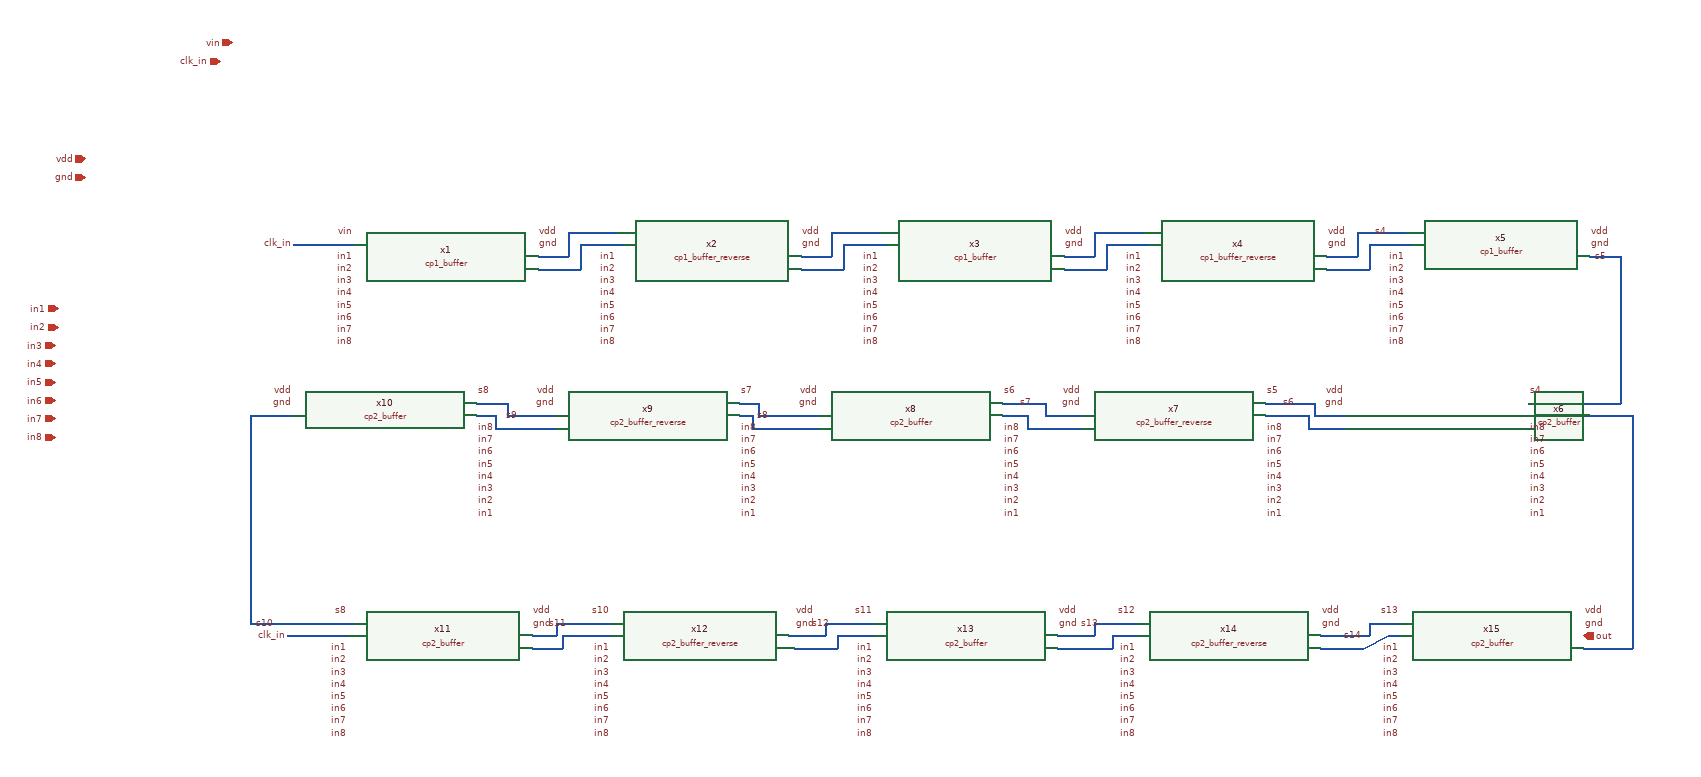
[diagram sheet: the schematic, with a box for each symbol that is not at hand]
v {xschem version=3.4.4 file_version=1.2
}
G {}
K {}
V {}
S {}
E {}
N -850 -580 -750 -580 {
lab=clk_in}
N -450 -560 -400 -560 {
lab=#net1}
N -400 -580 -400 -560 {
lab=#net1}
N -400 -600 -400 -580 {
lab=#net1}
N -400 -600 -320 -600 {
lab=#net1}
N -450 -540 -380 -540 {
lab=#net2}
N -380 -580 -380 -540 {
lab=#net2}
N -380 -580 -310 -580 {
lab=#net2}
N -20 -560 30 -560 {
lab=#net3}
N 30 -580 30 -560 {
lab=#net3}
N 30 -600 30 -580 {
lab=#net3}
N 30 -600 110 -600 {
lab=#net3}
N -20 -540 50 -540 {
lab=#net4}
N 50 -580 50 -540 {
lab=#net4}
N 50 -580 120 -580 {
lab=#net4}
N 410 -560 460 -560 {
lab=#net5}
N 460 -580 460 -560 {
lab=#net5}
N 460 -600 460 -580 {
lab=#net5}
N 460 -600 540 -600 {
lab=#net5}
N 410 -540 480 -540 {
lab=#net6}
N 480 -580 480 -540 {
lab=#net6}
N 480 -580 550 -580 {
lab=#net6}
N 840 -560 890 -560 {
lab=s4}
N 890 -580 890 -560 {
lab=s4}
N 890 -600 890 -580 {
lab=s4}
N 890 -600 970 -600 {
lab=s4}
N 840 -540 910 -540 {
lab=#net7}
N 910 -580 910 -540 {
lab=#net7}
N 910 -580 980 -580 {
lab=#net7}
N 1170 -300 1270 -300 {
lab=#net8}
N -860 60 -760 60 {
lab=clk_in}
N -500 -300 -420 -300 {
lab=s9}
N -500 -320 -500 -300 {
lab=s9}
N -540 -320 -500 -320 {
lab=s9}
N -550 -320 -540 -320 {
lab=s9}
N -90 -300 10 -300 {
lab=s8}
N -90 -320 -90 -300 {
lab=s8}
N -120 -320 -90 -320 {
lab=s8}
N -520 -280 -420 -280 {
lab=#net9}
N -520 -300 -520 -280 {
lab=#net9}
N -550 -300 -520 -300 {
lab=#net9}
N -100 -280 10 -280 {
lab=#net10}
N -100 -300 -100 -280 {
lab=#net10}
N -120 -300 -100 -300 {
lab=#net10}
N 350 -280 440 -280 {
lab=#net11}
N 350 -300 350 -280 {
lab=#net11}
N 310 -300 350 -300 {
lab=#net11}
N 810 -280 870 -280 {
lab=#net12}
N 810 -300 810 -280 {
lab=#net12}
N 740 -300 810 -300 {
lab=#net12}
N 1260 80 1340 80 {
lab=#net8}
N 1340 -300 1340 80 {
lab=#net8}
N 1260 -300 1340 -300 {
lab=#net8}
N 740 -320 820 -320 {
lab=s6}
N -460 80 -410 80 {
lab=#net13}
N -410 60 -410 80 {
lab=#net13}
N -410 60 -330 60 {
lab=#net13}
N -30 80 40 80 {
lab=#net14}
N 90 60 100 60 {
lab=#net14}
N 40 60 90 60 {
lab=#net14}
N 40 60 40 80 {
lab=#net14}
N 380 -300 440 -300 {
lab=s7}
N 380 -320 380 -300 {
lab=s7}
N 310 -320 380 -320 {
lab=s7}
N 1270 -560 1320 -560 {
lab=s5}
N 1320 -560 1320 -320 {
lab=s5}
N 1170 -320 1320 -320 {
lab=s5}
N -920 -300 -850 -300 {
lab=s10}
N -920 -300 -920 40 {
lab=s10}
N -920 40 -750 40 {
lab=s10}
N -460 60 -420 60 {
lab=s11}
N -420 40 -420 60 {
lab=s11}
N -420 40 -330 40 {
lab=s11}
N -40 60 -30 60 {
lab=s12}
N -30 60 20 60 {
lab=s12}
N 20 40 20 60 {
lab=s12}
N 20 40 100 40 {
lab=s12}
N 400 60 460 60 {
lab=s13}
N 460 40 460 60 {
lab=s13}
N 460 40 530 40 {
lab=s13}
N 830 60 910 60 {
lab=s14}
N 910 40 910 60 {
lab=s14}
N 910 40 960 40 {
lab=s14}
N 400 80 490 80 {
lab=#net15}
N 490 60 490 80 {
lab=#net15}
N 490 60 530 60 {
lab=#net15}
N 820 -320 820 -300 {
lab=s6}
N 820 -300 870 -300 {
lab=s6}
N 830 80 900 80 {
lab=#net16}
N 900 80 940 60 {
lab=#net16}
N 940 60 960 60 {
lab=#net16}
C {cp1_buffer.sym} -600 -510 0 0 {name=x1}
C {devices/lab_pin.sym} -750 -560 0 0 {name=p145 sig_type=std_logic lab=in1
value=0}
C {devices/lab_pin.sym} -750 -540 0 0 {name=p146 sig_type=std_logic lab=in2
value=0}
C {devices/lab_pin.sym} -750 -520 0 0 {name=p147 sig_type=std_logic lab=in3
value=0}
C {devices/lab_pin.sym} -750 -500 0 0 {name=p148 sig_type=std_logic lab=in4
value=0}
C {devices/lab_pin.sym} -750 -480 0 0 {name=p149 sig_type=std_logic lab=in5
value=0}
C {devices/lab_pin.sym} -750 -460 0 0 {name=p150 sig_type=std_logic lab=in6
value=0}
C {devices/lab_pin.sym} -750 -440 0 0 {name=p151 sig_type=std_logic lab=in7
value=0}
C {devices/lab_pin.sym} -750 -420 0 0 {name=p152 sig_type=std_logic lab=in8
value=0}
C {devices/lab_pin.sym} -750 -600 0 0 {name=p153 sig_type=std_logic lab=vin}
C {devices/lab_pin.sym} -850 -580 0 0 {name=p1 sig_type=std_logic lab=clk_in}
C {cp1_buffer.sym} 260 -510 0 0 {name=x3}
C {devices/lab_pin.sym} 110 -560 0 0 {name=p2 sig_type=std_logic lab=in1
value=0}
C {devices/lab_pin.sym} 110 -540 0 0 {name=p3 sig_type=std_logic lab=in2
value=0}
C {devices/lab_pin.sym} 110 -520 0 0 {name=p12 sig_type=std_logic lab=in3
value=0}
C {devices/lab_pin.sym} 110 -500 0 0 {name=p15 sig_type=std_logic lab=in4
value=0}
C {devices/lab_pin.sym} 110 -480 0 0 {name=p16 sig_type=std_logic lab=in5
value=0}
C {devices/lab_pin.sym} 110 -460 0 0 {name=p17 sig_type=std_logic lab=in6
value=0}
C {devices/lab_pin.sym} 110 -440 0 0 {name=p18 sig_type=std_logic lab=in7
value=0}
C {devices/lab_pin.sym} 110 -420 0 0 {name=p19 sig_type=std_logic lab=in8
value=0}
C {devices/lab_pin.sym} 410 -600 2 0 {name=p20 sig_type=std_logic lab=vdd}
C {devices/lab_pin.sym} 410 -580 2 0 {name=p21 sig_type=std_logic lab=gnd}
C {cp1_buffer.sym} 1120 -510 0 0 {name=x5}
C {devices/lab_pin.sym} 970 -560 0 0 {name=p28 sig_type=std_logic lab=in1
value=0}
C {devices/lab_pin.sym} 970 -540 0 0 {name=p29 sig_type=std_logic lab=in2
value=0}
C {devices/lab_pin.sym} 970 -520 0 0 {name=p30 sig_type=std_logic lab=in3
value=0}
C {devices/lab_pin.sym} 970 -500 0 0 {name=p31 sig_type=std_logic lab=in4
value=0}
C {devices/lab_pin.sym} 970 -480 0 0 {name=p32 sig_type=std_logic lab=in5
value=0}
C {devices/lab_pin.sym} 970 -460 0 0 {name=p33 sig_type=std_logic lab=in6
value=0}
C {devices/lab_pin.sym} 970 -440 0 0 {name=p34 sig_type=std_logic lab=in7
value=0}
C {devices/lab_pin.sym} 970 -420 0 0 {name=p35 sig_type=std_logic lab=in8
value=0}
C {devices/lab_pin.sym} 1270 -600 2 0 {name=p36 sig_type=std_logic lab=vdd}
C {devices/lab_pin.sym} 1270 -580 2 0 {name=p37 sig_type=std_logic lab=gnd}
C {devices/lab_pin.sym} -20 -600 2 0 {name=p38 sig_type=std_logic lab=vdd}
C {devices/lab_pin.sym} -20 -580 2 0 {name=p39 sig_type=std_logic lab=gnd}
C {devices/lab_pin.sym} -450 -600 2 0 {name=p40 sig_type=std_logic lab=vdd}
C {devices/lab_pin.sym} -450 -580 2 0 {name=p41 sig_type=std_logic lab=gnd}
C {devices/lab_pin.sym} 840 -600 2 0 {name=p42 sig_type=std_logic lab=vdd}
C {devices/lab_pin.sym} 840 -580 2 0 {name=p43 sig_type=std_logic lab=gnd}
C {cp2_buffer.sym} 1020 -240 0 1 {name=x6}
C {cp2_buffer_reverse.sym} 590 -240 0 1 {name=x7}
C {cp2_buffer.sym} 160 -240 0 1 {name=x8}
C {devices/lab_pin.sym} 10 -340 2 1 {name=p70 sig_type=std_logic lab=vdd}
C {devices/lab_pin.sym} 10 -320 2 1 {name=p71 sig_type=std_logic lab=gnd}
C {cp2_buffer_reverse.sym} -270 -240 0 1 {name=x9}
C {cp2_buffer.sym} -700 -240 0 1 {name=x10}
C {devices/lab_pin.sym} -850 -340 2 1 {name=p88 sig_type=std_logic lab=vdd}
C {devices/lab_pin.sym} -850 -320 2 1 {name=p89 sig_type=std_logic lab=gnd}
C {devices/lab_pin.sym} 440 -340 2 1 {name=p90 sig_type=std_logic lab=vdd}
C {devices/lab_pin.sym} 440 -320 2 1 {name=p91 sig_type=std_logic lab=gnd}
C {devices/lab_pin.sym} 870 -340 2 1 {name=p92 sig_type=std_logic lab=vdd}
C {devices/lab_pin.sym} 870 -320 2 1 {name=p93 sig_type=std_logic lab=gnd}
C {devices/lab_pin.sym} -420 -340 2 1 {name=p94 sig_type=std_logic lab=vdd}
C {devices/lab_pin.sym} -420 -320 2 1 {name=p95 sig_type=std_logic lab=gnd}
C {cp2_buffer.sym} -610 120 0 0 {name=x11}
C {devices/lab_pin.sym} -760 80 0 0 {name=p96 sig_type=std_logic lab=in1
value=0}
C {devices/lab_pin.sym} -760 100 0 0 {name=p97 sig_type=std_logic lab=in2
value=0}
C {devices/lab_pin.sym} -760 120 0 0 {name=p98 sig_type=std_logic lab=in3
value=0}
C {devices/lab_pin.sym} -760 140 0 0 {name=p99 sig_type=std_logic lab=in4
value=0}
C {devices/lab_pin.sym} -760 160 0 0 {name=p100 sig_type=std_logic lab=in5
value=0}
C {devices/lab_pin.sym} -760 180 0 0 {name=p101 sig_type=std_logic lab=in6
value=0}
C {devices/lab_pin.sym} -760 200 0 0 {name=p102 sig_type=std_logic lab=in7
value=0}
C {devices/lab_pin.sym} -760 220 0 0 {name=p103 sig_type=std_logic lab=in8
value=0}
C {devices/lab_pin.sym} -860 60 0 0 {name=p105 sig_type=std_logic lab=clk_in}
C {cp2_buffer_reverse.sym} -180 120 0 0 {name=x12}
C {devices/lab_pin.sym} -330 80 0 0 {name=p106 sig_type=std_logic lab=in1
value=0}
C {devices/lab_pin.sym} -330 100 0 0 {name=p107 sig_type=std_logic lab=in2
value=0}
C {devices/lab_pin.sym} -330 120 0 0 {name=p108 sig_type=std_logic lab=in3
value=0}
C {devices/lab_pin.sym} -330 140 0 0 {name=p109 sig_type=std_logic lab=in4
value=0}
C {devices/lab_pin.sym} -330 160 0 0 {name=p110 sig_type=std_logic lab=in5
value=0}
C {devices/lab_pin.sym} -330 180 0 0 {name=p111 sig_type=std_logic lab=in6
value=0}
C {devices/lab_pin.sym} -330 200 0 0 {name=p112 sig_type=std_logic lab=in7
value=0}
C {devices/lab_pin.sym} -330 220 0 0 {name=p113 sig_type=std_logic lab=in8
value=0}
C {cp2_buffer.sym} 250 120 0 0 {name=x13}
C {devices/lab_pin.sym} 100 80 0 0 {name=p114 sig_type=std_logic lab=in1
value=0}
C {devices/lab_pin.sym} 100 100 0 0 {name=p115 sig_type=std_logic lab=in2
value=0}
C {devices/lab_pin.sym} 100 120 0 0 {name=p116 sig_type=std_logic lab=in3
value=0}
C {devices/lab_pin.sym} 100 140 0 0 {name=p117 sig_type=std_logic lab=in4
value=0}
C {devices/lab_pin.sym} 100 160 0 0 {name=p118 sig_type=std_logic lab=in5
value=0}
C {devices/lab_pin.sym} 100 180 0 0 {name=p119 sig_type=std_logic lab=in6
value=0}
C {devices/lab_pin.sym} 100 200 0 0 {name=p120 sig_type=std_logic lab=in7
value=0}
C {devices/lab_pin.sym} 100 220 0 0 {name=p121 sig_type=std_logic lab=in8
value=0}
C {devices/lab_pin.sym} 400 20 2 0 {name=p122 sig_type=std_logic lab=vdd}
C {devices/lab_pin.sym} 400 40 2 0 {name=p123 sig_type=std_logic lab=gnd}
C {cp2_buffer_reverse.sym} 680 120 0 0 {name=x14}
C {devices/lab_pin.sym} 530 80 0 0 {name=p124 sig_type=std_logic lab=in1
value=0}
C {devices/lab_pin.sym} 530 100 0 0 {name=p125 sig_type=std_logic lab=in2
value=0}
C {devices/lab_pin.sym} 530 120 0 0 {name=p126 sig_type=std_logic lab=in3
value=0}
C {devices/lab_pin.sym} 530 140 0 0 {name=p127 sig_type=std_logic lab=in4
value=0}
C {devices/lab_pin.sym} 530 160 0 0 {name=p128 sig_type=std_logic lab=in5
value=0}
C {devices/lab_pin.sym} 530 180 0 0 {name=p129 sig_type=std_logic lab=in6
value=0}
C {devices/lab_pin.sym} 530 200 0 0 {name=p130 sig_type=std_logic lab=in7
value=0}
C {devices/lab_pin.sym} 530 220 0 0 {name=p131 sig_type=std_logic lab=in8
value=0}
C {cp2_buffer.sym} 1110 120 0 0 {name=x15}
C {devices/lab_pin.sym} 960 80 0 0 {name=p132 sig_type=std_logic lab=in1
value=0}
C {devices/lab_pin.sym} 960 100 0 0 {name=p133 sig_type=std_logic lab=in2
value=0}
C {devices/lab_pin.sym} 960 120 0 0 {name=p134 sig_type=std_logic lab=in3
value=0}
C {devices/lab_pin.sym} 960 140 0 0 {name=p135 sig_type=std_logic lab=in4
value=0}
C {devices/lab_pin.sym} 960 160 0 0 {name=p136 sig_type=std_logic lab=in5
value=0}
C {devices/lab_pin.sym} 960 180 0 0 {name=p137 sig_type=std_logic lab=in6
value=0}
C {devices/lab_pin.sym} 960 200 0 0 {name=p138 sig_type=std_logic lab=in7
value=0}
C {devices/lab_pin.sym} 960 220 0 0 {name=p139 sig_type=std_logic lab=in8
value=0}
C {devices/lab_pin.sym} 1260 20 2 0 {name=p140 sig_type=std_logic lab=vdd}
C {devices/lab_pin.sym} 1260 40 2 0 {name=p141 sig_type=std_logic lab=gnd}
C {devices/lab_pin.sym} -30 20 2 0 {name=p142 sig_type=std_logic lab=vdd}
C {devices/lab_pin.sym} -30 40 2 0 {name=p143 sig_type=std_logic lab=gnd}
C {devices/lab_pin.sym} -460 20 2 0 {name=p144 sig_type=std_logic lab=vdd}
C {devices/lab_pin.sym} -460 40 2 0 {name=p154 sig_type=std_logic lab=gnd}
C {devices/lab_pin.sym} 830 20 2 0 {name=p155 sig_type=std_logic lab=vdd}
C {devices/lab_pin.sym} 830 40 2 0 {name=p156 sig_type=std_logic lab=gnd}
C {devices/lab_pin.sym} 1300 -560 3 0 {name=p53 sig_type=std_logic lab=s5}
C {devices/lab_pin.sym} 790 -320 1 0 {name=p104 sig_type=std_logic lab=s6}
C {devices/lab_pin.sym} 360 -320 1 0 {name=p157 sig_type=std_logic lab=s7}
C {devices/lab_pin.sym} -70 -300 1 0 {name=p158 sig_type=std_logic lab=s8}
C {devices/lab_pin.sym} -480 -300 1 0 {name=p159 sig_type=std_logic lab=s9}
C {devices/lab_pin.sym} -880 40 1 0 {name=p160 sig_type=std_logic lab=s10}
C {devices/lab_pin.sym} -400 40 1 0 {name=p161 sig_type=std_logic lab=s11}
C {devices/lab_pin.sym} 30 40 1 0 {name=p162 sig_type=std_logic lab=s12}
C {devices/lab_pin.sym} 470 40 1 0 {name=p163 sig_type=std_logic lab=s13}
C {devices/lab_pin.sym} 900 60 1 0 {name=p164 sig_type=std_logic lab=s14}
C {devices/lab_pin.sym} 1170 -340 2 0 {name=p165 sig_type=std_logic lab=s4}
C {devices/lab_pin.sym} 740 -340 0 1 {name=p166 sig_type=std_logic lab=s5}
C {devices/lab_pin.sym} 310 -340 2 0 {name=p167 sig_type=std_logic lab=s6}
C {devices/lab_pin.sym} -120 -340 2 0 {name=p168 sig_type=std_logic lab=s7}
C {devices/lab_pin.sym} -550 -340 2 0 {name=p169 sig_type=std_logic lab=s8}
C {devices/lab_pin.sym} -760 20 0 0 {name=p170 sig_type=std_logic lab=s8}
C {devices/lab_pin.sym} -330 20 0 0 {name=p171 sig_type=std_logic lab=s10}
C {devices/lab_pin.sym} 100 20 0 0 {name=p172 sig_type=std_logic lab=s11}
C {devices/lab_pin.sym} 530 20 0 0 {name=p173 sig_type=std_logic lab=s12}
C {devices/lab_pin.sym} 960 20 0 0 {name=p174 sig_type=std_logic lab=s13}
C {devices/ipin.sym} -1235 -475 0 0 {name=p175 lab=in1}
C {devices/ipin.sym} -1235 -445 0 0 {name=p176 lab=in2}
C {devices/ipin.sym} -1240 -415 0 0 {name=p177 lab=in3}
C {devices/ipin.sym} -1240 -385 0 0 {name=p178 lab=in4}
C {devices/ipin.sym} -1240 -355 0 0 {name=p179 lab=in5}
C {devices/ipin.sym} -1240 -325 0 0 {name=p180 lab=in6}
C {devices/ipin.sym} -1240 -295 0 0 {name=p181 lab=in7}
C {devices/ipin.sym} -1240 -265 0 0 {name=p182 lab=in8}
C {devices/iopin.sym} -1190 -690 0 0 {name=p183 lab=gnd}
C {devices/iopin.sym} -1190 -720 0 0 {name=p184 lab=vdd}
C {devices/ipin.sym} -950 -910 0 0 {name=p185 lab=vin}
C {devices/ipin.sym} -970 -880 0 0 {name=p186 lab=clk_in}
C {devices/opin.sym} 1260 60 0 0 {name=p187 lab=out}
C {devices/lab_pin.sym} -320 -560 0 0 {name=p188 sig_type=std_logic lab=in1
value=0}
C {devices/lab_pin.sym} -320 -540 0 0 {name=p189 sig_type=std_logic lab=in2
value=0}
C {devices/lab_pin.sym} -320 -520 0 0 {name=p190 sig_type=std_logic lab=in3
value=0}
C {devices/lab_pin.sym} -320 -500 0 0 {name=p191 sig_type=std_logic lab=in4
value=0}
C {devices/lab_pin.sym} -320 -480 0 0 {name=p192 sig_type=std_logic lab=in5
value=0}
C {devices/lab_pin.sym} -320 -460 0 0 {name=p193 sig_type=std_logic lab=in6
value=0}
C {devices/lab_pin.sym} -320 -440 0 0 {name=p194 sig_type=std_logic lab=in7
value=0}
C {devices/lab_pin.sym} -320 -420 0 0 {name=p195 sig_type=std_logic lab=in8
value=0}
C {devices/lab_pin.sym} 540 -560 0 0 {name=p13 sig_type=std_logic lab=in1
value=0}
C {devices/lab_pin.sym} 540 -540 0 0 {name=p14 sig_type=std_logic lab=in2
value=0}
C {devices/lab_pin.sym} 540 -520 0 0 {name=p22 sig_type=std_logic lab=in3
value=0}
C {devices/lab_pin.sym} 540 -500 0 0 {name=p23 sig_type=std_logic lab=in4
value=0}
C {devices/lab_pin.sym} 540 -480 0 0 {name=p24 sig_type=std_logic lab=in5
value=0}
C {devices/lab_pin.sym} 540 -460 0 0 {name=p25 sig_type=std_logic lab=in6
value=0}
C {devices/lab_pin.sym} 540 -440 0 0 {name=p26 sig_type=std_logic lab=in7
value=0}
C {devices/lab_pin.sym} 540 -420 0 0 {name=p27 sig_type=std_logic lab=in8
value=0}
C {cp1_buffer_reverse.sym} -170 -510 0 0 {name=x2}
C {cp1_buffer_reverse.sym} 690 -510 0 0 {name=x4}
C {devices/lab_pin.sym} -550 -140 2 0 {name=p44 sig_type=std_logic lab=in1
value=0}
C {devices/lab_pin.sym} -550 -160 2 0 {name=p45 sig_type=std_logic lab=in2
value=0}
C {devices/lab_pin.sym} -550 -180 2 0 {name=p46 sig_type=std_logic lab=in3
value=0}
C {devices/lab_pin.sym} -550 -200 2 0 {name=p47 sig_type=std_logic lab=in4
value=0}
C {devices/lab_pin.sym} -550 -220 2 0 {name=p48 sig_type=std_logic lab=in5
value=0}
C {devices/lab_pin.sym} -550 -240 2 0 {name=p49 sig_type=std_logic lab=in6
value=0}
C {devices/lab_pin.sym} -550 -260 2 0 {name=p50 sig_type=std_logic lab=in7
value=0}
C {devices/lab_pin.sym} -550 -280 2 0 {name=p51 sig_type=std_logic lab=in8
value=0}
C {devices/lab_pin.sym} -120 -140 2 0 {name=p54 sig_type=std_logic lab=in1
value=0}
C {devices/lab_pin.sym} -120 -160 2 0 {name=p55 sig_type=std_logic lab=in2
value=0}
C {devices/lab_pin.sym} -120 -180 2 0 {name=p56 sig_type=std_logic lab=in3
value=0}
C {devices/lab_pin.sym} -120 -200 2 0 {name=p57 sig_type=std_logic lab=in4
value=0}
C {devices/lab_pin.sym} -120 -220 2 0 {name=p58 sig_type=std_logic lab=in5
value=0}
C {devices/lab_pin.sym} -120 -240 2 0 {name=p59 sig_type=std_logic lab=in6
value=0}
C {devices/lab_pin.sym} -120 -260 2 0 {name=p60 sig_type=std_logic lab=in7
value=0}
C {devices/lab_pin.sym} -120 -280 2 0 {name=p61 sig_type=std_logic lab=in8
value=0}
C {devices/lab_pin.sym} 310 -140 2 0 {name=p62 sig_type=std_logic lab=in1
value=0}
C {devices/lab_pin.sym} 310 -160 2 0 {name=p63 sig_type=std_logic lab=in2
value=0}
C {devices/lab_pin.sym} 310 -180 2 0 {name=p64 sig_type=std_logic lab=in3
value=0}
C {devices/lab_pin.sym} 310 -200 2 0 {name=p65 sig_type=std_logic lab=in4
value=0}
C {devices/lab_pin.sym} 310 -220 2 0 {name=p66 sig_type=std_logic lab=in5
value=0}
C {devices/lab_pin.sym} 310 -240 2 0 {name=p67 sig_type=std_logic lab=in6
value=0}
C {devices/lab_pin.sym} 310 -260 2 0 {name=p68 sig_type=std_logic lab=in7
value=0}
C {devices/lab_pin.sym} 310 -280 2 0 {name=p69 sig_type=std_logic lab=in8
value=0}
C {devices/lab_pin.sym} 740 -140 2 0 {name=p72 sig_type=std_logic lab=in1
value=0}
C {devices/lab_pin.sym} 740 -160 2 0 {name=p73 sig_type=std_logic lab=in2
value=0}
C {devices/lab_pin.sym} 740 -180 2 0 {name=p74 sig_type=std_logic lab=in3
value=0}
C {devices/lab_pin.sym} 740 -200 2 0 {name=p75 sig_type=std_logic lab=in4
value=0}
C {devices/lab_pin.sym} 740 -220 2 0 {name=p76 sig_type=std_logic lab=in5
value=0}
C {devices/lab_pin.sym} 740 -240 2 0 {name=p77 sig_type=std_logic lab=in6
value=0}
C {devices/lab_pin.sym} 740 -260 2 0 {name=p78 sig_type=std_logic lab=in7
value=0}
C {devices/lab_pin.sym} 740 -280 2 0 {name=p79 sig_type=std_logic lab=in8
value=0}
C {devices/lab_pin.sym} 1170 -140 2 0 {name=p80 sig_type=std_logic lab=in1
value=0}
C {devices/lab_pin.sym} 1170 -160 2 0 {name=p81 sig_type=std_logic lab=in2
value=0}
C {devices/lab_pin.sym} 1170 -180 2 0 {name=p82 sig_type=std_logic lab=in3
value=0}
C {devices/lab_pin.sym} 1170 -200 2 0 {name=p83 sig_type=std_logic lab=in4
value=0}
C {devices/lab_pin.sym} 1170 -220 2 0 {name=p84 sig_type=std_logic lab=in5
value=0}
C {devices/lab_pin.sym} 1170 -240 2 0 {name=p85 sig_type=std_logic lab=in6
value=0}
C {devices/lab_pin.sym} 1170 -260 2 0 {name=p86 sig_type=std_logic lab=in7
value=0}
C {devices/lab_pin.sym} 1170 -280 2 0 {name=p87 sig_type=std_logic lab=in8
value=0}
C {devices/lab_pin.sym} 940 -600 1 0 {name=p52 sig_type=std_logic lab=s4}
